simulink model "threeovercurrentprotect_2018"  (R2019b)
settings: Solver=ode23t  StartTime=0.0  StopTime=2  MaxStep=1/50/100  RelTol=1e-3
libraries: powerlib x13

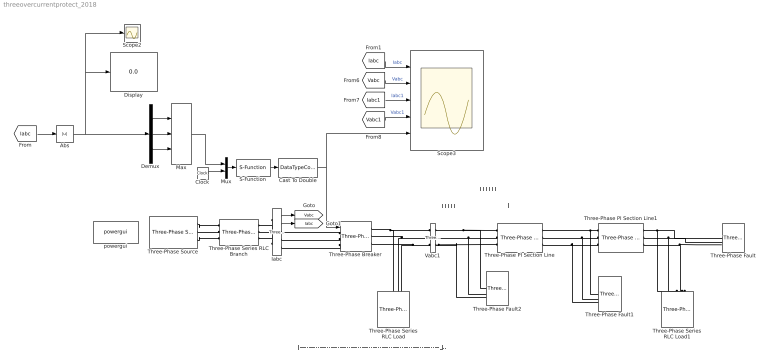
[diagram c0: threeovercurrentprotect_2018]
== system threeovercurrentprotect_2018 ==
  note: |-------------------一段保护范围-----------------------------|
  note: |--------------------------------------------------------二段保护范围--------------------------------------------------|
  note: |-----------------------------------------------------------------------------三段保护范围---------------------------------------------------------------------------|
  Abs : Abs
  Cast To Double : DataTypeConversion  OutDataTypeStr=double
  Clock : Clock
  Demux : Demux  Outputs=3
  Display : Display
  Iabc : powerlib/Measurements/Three-Phase V-I Measurement  VoltageMeasurement=phase-to-ground  SetLabelV=off  LabelV=Vabc  Vpu=off  VpuLL=off  CurrentMeasurement=yes  SetLabelI=off  LabelI=Iabc  Ipu=off  Pbase=100e6  Vbase=500e3  OutputType=Complex  PhasorSimulation=off  PSBequivalent=0
  Max : MinMax  Function=max  Inputs=3
  Mux : Mux  Inputs=2
  S-Function : S-Function  FunctionName=modbusCom1  SFunctionDeploymentMode=off  EnableBusSupport=off
  Scope2 : Scope
  Scope3 : Scope  NumInputPorts=5
  Three-Phase PI Section Line : powerlib/Elements/Three-Phase PI Section Line  LConnTagsString=a|b|c  RConnTagsString=A|B|C  Frequency=50  Resistances=[ 0.01273 0.3864]  Inductances="[ 0.9337e-3  4.1264e-3]"  Capacitances=[12.74e-9 7.751e-9]  Length=3
  Three-Phase PI Section Line1 : powerlib/Elements/Three-Phase PI Section Line  LConnTagsString=a|b|c  RConnTagsString=A|B|C  Frequency=50  Resistances=[ 0.01273 0.3864]  Inductances="[ 0.9337e-3  4.1264e-3]"  Capacitances=[12.74e-9 7.751e-9]  Length=1
  Three-Phase Series RLC Branch : powerlib/Elements/Three-Phase Series RLC Branch  LConnTagsString=A|B|C  RConnTagsString=A|B|C  BranchType=RL  Resistance=1e-3  Inductance=1e-6  Capacitance=1e-6  Measurements=None
  Three-Phase Series RLC Load : powerlib/Elements/Three-Phase Series RLC Load  LConnTagsString=A|B|C  Configuration=Y (grounded)  NominalVoltage=380  Vabc=[1e3 1e3 1e3]  Vabcp=[1e3 1e3 1e3]  NominalFrequency=50  UnbalancedPower=off  ActivePower=20e3  InductivePower=1000  CapacitivePower=100  Pabc=[10e3 9e3 11e3]  QLabc=[100 90 110]  QCabc=[100 90 110]  Pabcp=[10e3 9e3 11e3]  QLabcp=[100 90 110]  QCabcp=[100 90 110]  Measurements=None  LoadType=constant Z
  Three-Phase Series RLC Load1 : powerlib/Elements/Three-Phase Series RLC Load  LConnTagsString=A|B|C  Configuration=Y (grounded)  NominalVoltage=380  Vabc=[1e3 1e3 1e3]  Vabcp=[1e3 1e3 1e3]  NominalFrequency=50  UnbalancedPower=off  ActivePower=20e3  InductivePower=1000  CapacitivePower=100  Pabc=[10e3 9e3 11e3]  QLabc=[100 90 110]  QCabc=[100 90 110]  Pabcp=[10e3 9e3 11e3]  QLabcp=[100 90 110]  QCabcp=[100 90 110]  Measurements=None  LoadType=constant Z
  Three-Phase Breaker : powerlib/Elements/Three-Phase Breaker  InitialState=closed  SwitchA=on  SwitchB=on  SwitchC=on  SwitchTimes="[1/60  5/60]"  External=on  BreakerResistance=0.01  SnubberResistance=1e6  SnubberCapacitance=inf  Measurements=None
  Three-Phase Fault : powerlib/Elements/Three-Phase Fault  Commented=on  InitialStates=0  FaultA=on  FaultB=off  FaultC=off  GroundFault=on  SwitchTimes="[0.1  1]"  External=off  SwitchStatus=NaN  FaultResistance=0.001  GroundResistance=0.01  SnubberResistance=1e6  SnubberCapacitance=inf  Measurements=None
  Three-Phase Fault1 : powerlib/Elements/Three-Phase Fault  Commented=on  InitialStates=0  FaultA=on  FaultB=off  FaultC=off  GroundFault=on  SwitchTimes="[0.1  1]"  External=off  SwitchStatus=NaN  FaultResistance=0.001  GroundResistance=0.01  SnubberResistance=1e6  SnubberCapacitance=inf  Measurements=None
  Three-Phase Fault2 : powerlib/Elements/Three-Phase Fault  Commented=on  InitialStates=0  FaultA=on  FaultB=off  FaultC=off  GroundFault=on  SwitchTimes="[0.1  1]"  External=off  SwitchStatus=NaN  FaultResistance=0.001  GroundResistance=0.01  SnubberResistance=1e6  SnubberCapacitance=inf  Measurements=None
  Three-Phase Source : powerlib/Electrical Sources/Three-Phase Source  InternalConnection=Yg  VoltagePhases=off  Voltage=380  PhaseAngle=0  Voltage_phases=[25e3 25e3 25e3]/sqrt(3)  PhaseAngles_phases=[0 -120 +120]  Frequency=50  NonIdealSource=on  SpecifyImpedance=on  Resistance=0.8929  Inductance=16.58e-6  ShortCircuitLevel=1e6  BaseVoltage=380  XRratio=7  BusType=swing  Pref=10e3  Qref=0  Prefabc=[10e3, 10e3, 10e3]  Qrefabc=[0, 0, 0]  Qmin=-inf  Qmax=inf
  Vabc1 : powerlib/Measurements/Three-Phase V-I Measurement  VoltageMeasurement=phase-to-ground  SetLabelV=on  LabelV=Vabc1  Vpu=off  VpuLL=off  CurrentMeasurement=yes  SetLabelI=on  LabelI=Iabc1  Ipu=off  Pbase=100e6  Vbase=500e3  OutputType=Complex  PhasorSimulation=off  PSBequivalent=0
  powergui : powerlib/powergui  Priority=1  SimulationMode=Discrete  SampleTime=50e-6  frequency=60  Iterations=50  frequencyindice=0  Pbase=100e6  ErrMax=1e-4  UnitsV=kV  UnitsW=MW  buscounter=0  FunctionMessages=off  echomessages=off  EnableUseOfTLC=off  CurrentSourceSwitches=off  DisableSnubberDevices=off  DisableRonSwitches=off  DisableVfSwitches=off  DisplayEquations=off  AutomaticDiscreteSolvers=off  SolverType=Tustin/Backward Euler (TBE)  Interpol=off  ExternalGateDelay=off  methode=off  Ts=100  x0status=blocks  SPID=on  SwTol=0  HookPort=off  NonlinearTolerance=1e-4  nMaxIteration=100  ContinueOnMaxIteration=off  RestoreLinks=warning  ResistiveCurrentMeasurement=off  Frange=[0:2:500]  Ylog=off  Xlog=on  ShowGrid=off  save=off  variable=ZData  structure=0  ZoomFFT=off  StartTime=0.0  cycles=1  DisplayStyle=1  fundamental=60  FreqAxis=off  MaxFrequency=1000  frequencyindicesteady=1  RmsSteady=1  display=off
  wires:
  [Iabc] -> Scope3/1  "Iabc"
  [Vabc] -> Scope3/2  "Vabc"
  [Iabc1] -> Scope3/3  "Iabc1"
  [Vabc1] -> Scope3/4  "Vabc1"
  Iabc/1 -> [Vabc]
  Iabc/2 -> [Iabc]
  Demux/1 -> Max/1
  Demux/2 -> Max/2
  Demux/3 -> Max/3
  S-Function/1 -> Cast To Double/1
  Cast To Double/1 -> Scope3/5, Three-Phase Breaker/1
  Clock/1 -> Mux/2
  Mux/1 -> S-Function/1
  Max/1 -> Mux/1
  [Iabc] -> Abs/1
  Abs/1 -> Scope2/1, Display/1, Demux/1
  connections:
  Three-Phase Series RLC Branch/LConn2 -- Three-Phase Source/RConn2
  Three-Phase Source/RConn1 -- Three-Phase Series RLC Branch/LConn1
  Three-Phase Source/RConn3 -- Three-Phase Series RLC Branch/LConn3
  Three-Phase Breaker/LConn1 -- Iabc/RConn1
  Three-Phase Breaker/LConn2 -- Iabc/RConn2
  Three-Phase Breaker/LConn3 -- Iabc/RConn3
  Vabc1/LConn1 -- Three-Phase Series RLC Load/LConn1 -- Three-Phase Breaker/RConn1
  Vabc1/LConn2 -- Three-Phase Series RLC Load/LConn2 -- Three-Phase Breaker/RConn2
  Vabc1/LConn3 -- Three-Phase Series RLC Load/LConn3 -- Three-Phase Breaker/RConn3
  Three-Phase PI Section Line/LConn2 -- Three-Phase Fault2/LConn2 -- Vabc1/RConn2
  Vabc1/RConn1 -- Three-Phase Fault2/LConn1 -- Three-Phase PI Section Line/LConn1
  Vabc1/RConn3 -- Three-Phase Fault2/LConn3 -- Three-Phase PI Section Line/LConn3
  Three-Phase PI Section Line1/LConn1 -- Three-Phase Fault1/LConn1 -- Three-Phase PI Section Line/RConn1
  Three-Phase PI Section Line1/LConn2 -- Three-Phase Fault1/LConn2 -- Three-Phase PI Section Line/RConn2
  Three-Phase PI Section Line1/LConn3 -- Three-Phase Fault1/LConn3 -- Three-Phase PI Section Line/RConn3
  Three-Phase PI Section Line1/RConn1 -- Three-Phase Fault/LConn1 -- Three-Phase Series RLC Load1/LConn1
  Three-Phase PI Section Line1/RConn2 -- Three-Phase Fault/LConn2 -- Three-Phase Series RLC Load1/LConn2
  Three-Phase PI Section Line1/RConn3 -- Three-Phase Fault/LConn3 -- Three-Phase Series RLC Load1/LConn3
  Iabc/LConn1 -- Three-Phase Series RLC Branch/RConn1
  Iabc/LConn2 -- Three-Phase Series RLC Branch/RConn2
  Iabc/LConn3 -- Three-Phase Series RLC Branch/RConn3
